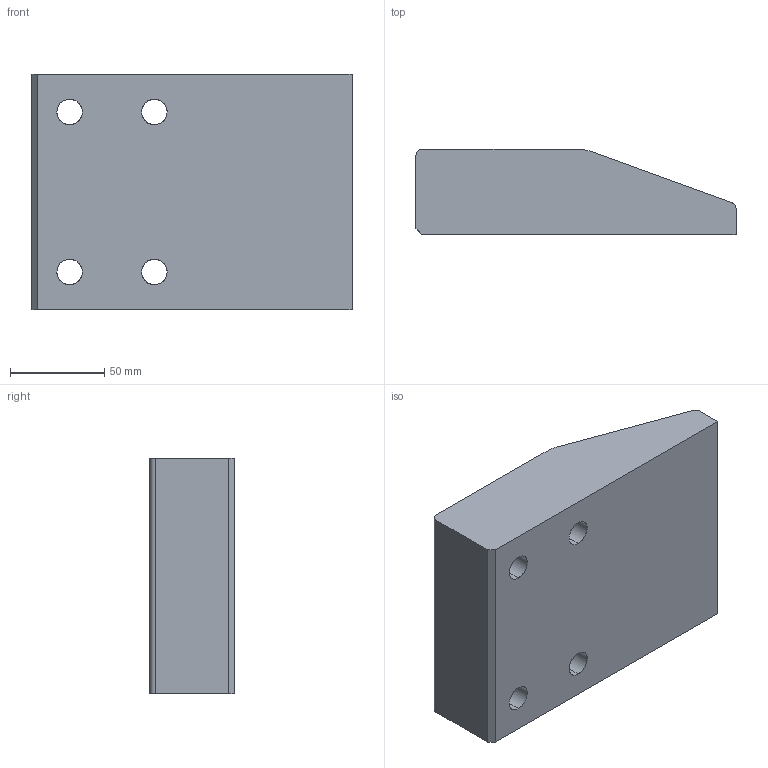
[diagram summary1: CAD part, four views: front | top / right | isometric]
STEP (ISO 10303-21) file: header records copied from the file, then geometry measured from it (millimetres).
FILE_DESCRIPTION(('CATIA V5 STEP Exchange'),'2;1');
FILE_NAME('C:\Users\Utente\Desktop\3D files A934\A934-12517045.stp','2020-04-17T08:27:25+00:00',('none'),('none'),'CATIA Version 5 Release 20 GA (IN-10)','CATIA V5 STEP AP203','none');
FILE_SCHEMA(('CONFIG_CONTROL_DESIGN'));
Length unit declared in the file: millimetre
Products named in the file (1): Noname
Bounding box: 170 x 45 x 125 mm (x, y, z)
Surface area: 71884.9 mm2 (no closed solid volume)
Topology: 0 solids, 27 shells, 39 faces, 158 edges, 134 vertices
Faces by surface type: cylinder 19, extrusion 12, revolution 8
Entity records: 2130 total; most frequent: CARTESIAN_POINT 868, ORIENTED_EDGE 182, DIRECTION 174, EDGE_CURVE 158, VERTEX_POINT 134, AXIS2_PLACEMENT_3D 82, VECTOR 66, B_SPLINE_CURVE_WITH_KNOTS 62
One B-rep face of a CAD part: STEP entity #93.
In plain terms, the face is a extrusion surface.
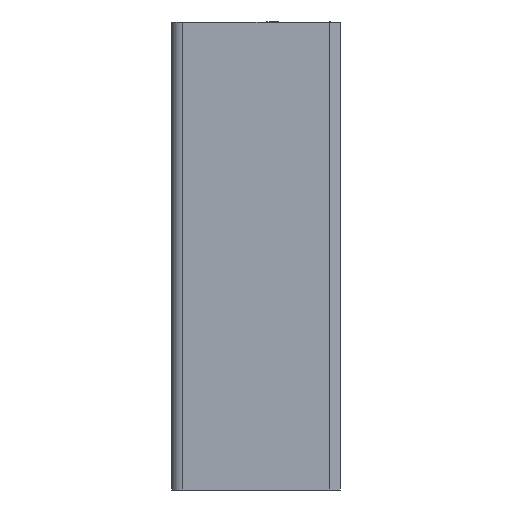
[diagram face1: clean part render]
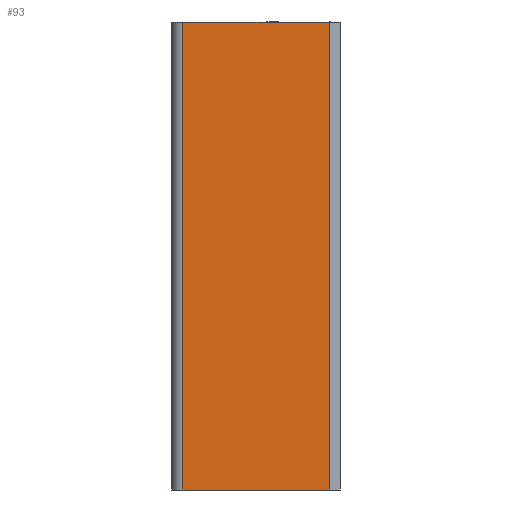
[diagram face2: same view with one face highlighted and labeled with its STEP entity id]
Its self-contained STEP definition (entity closure, numbers rounded to 3 decimals):
#54=CARTESIAN_POINT('Control Point',(0.,3.,-125.)) ;
#55=CARTESIAN_POINT('Control Point',(0.,3.,0.)) ;
#59=CARTESIAN_POINT('Line Origine',(0.,22.5,0.)) ;
#63=CARTESIAN_POINT('Vertex',(0.,3.,0.)) ;
#65=CARTESIAN_POINT('Vertex',(0.,42.,0.)) ;
#68=CARTESIAN_POINT('Line Origine',(0.,42.,-62.5)) ;
#72=CARTESIAN_POINT('Vertex',(0.,42.,-125.)) ;
#75=CARTESIAN_POINT('Line Origine',(0.,22.5,-125.)) ;
#79=CARTESIAN_POINT('Vertex',(0.,3.,-125.)) ;
#82=CARTESIAN_POINT('Line Origine',(0.,3.,-62.5)) ;
#56=DIRECTION('Vector Direction',(0.,1.,0.)) ;
#60=DIRECTION('Vector Direction',(0.,1.,0.)) ;
#69=DIRECTION('Vector Direction',(0.,0.,1.)) ;
#76=DIRECTION('Vector Direction',(0.,1.,0.)) ;
#83=DIRECTION('Vector Direction',(0.,0.,1.)) ;
#88=ORIENTED_EDGE('',*,*,#67,.T.) ;
#89=ORIENTED_EDGE('',*,*,#74,.T.) ;
#90=ORIENTED_EDGE('',*,*,#81,.T.) ;
#91=ORIENTED_EDGE('',*,*,#86,.T.) ;
#57=VECTOR('Extrusion Surface Vector',#56,1.) ;
#61=VECTOR('Line Direction',#60,1.) ;
#70=VECTOR('Line Direction',#69,1.) ;
#77=VECTOR('Line Direction',#76,1.) ;
#84=VECTOR('Line Direction',#83,1.) ;
#93=ADVANCED_FACE('Superficie.1',(#92),#58,.T.) ;
#53=B_SPLINE_CURVE_WITH_KNOTS('',1,(#54,#55),.UNSPECIFIED.,.F.,.U.,(2,2),(-62.5,62.5),.UNSPECIFIED.) ;
#67=EDGE_CURVE('',#64,#66,#62,.T.) ;
#74=EDGE_CURVE('',#66,#73,#71,.F.) ;
#81=EDGE_CURVE('',#73,#80,#78,.F.) ;
#86=EDGE_CURVE('',#80,#64,#85,.T.) ;
#87=EDGE_LOOP('',(#88,#89,#90,#91)) ;
#92=FACE_OUTER_BOUND('',#87,.T.) ;
#62=LINE('Line',#59,#61) ;
#71=LINE('Line',#68,#70) ;
#78=LINE('Line',#75,#77) ;
#85=LINE('Line',#82,#84) ;
#58=SURFACE_OF_LINEAR_EXTRUSION('generated tabulated cylinder',#53,#57) ;
#64=VERTEX_POINT('',#63) ;
#66=VERTEX_POINT('',#65) ;
#73=VERTEX_POINT('',#72) ;
#80=VERTEX_POINT('',#79) ;
